VERSION 5.7 ;
  NOWIREEXTENSIONATPIN ON ;
  DIVIDERCHAR "/" ;
  BUSBITCHARS "[]" ;
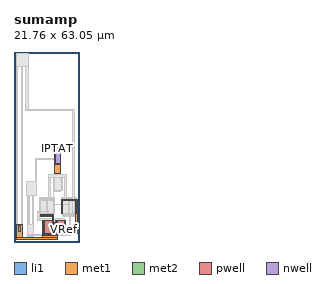
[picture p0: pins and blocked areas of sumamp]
MACRO sumamp
  CLASS BLOCK ;
  FOREIGN sumamp ;
  ORIGIN -0.630 -0.510 ;
  SIZE 21.760 BY 63.050 ;
  PIN IPTAT
    ANTENNAGATEAREA 4.000000 ;
    PORT
      LAYER li1 ;
        RECT 14.485 30.945 15.485 31.175 ;
      LAYER met1 ;
        RECT 14.015 30.920 15.935 32.040 ;
    END
  END IPTAT
  PIN VRef
    ANTENNAGATEAREA 16.000000 ;
    ANTENNADIFFAREA 3.180000 ;
    PORT
      LAYER li1 ;
        RECT 16.485 10.110 16.655 14.110 ;
        RECT 21.045 10.110 21.215 14.110 ;
        RECT 9.485 9.270 13.765 9.500 ;
        RECT 17.305 3.370 17.475 7.370 ;
      LAYER met1 ;
        RECT 16.455 14.460 21.245 14.510 ;
        RECT 16.455 14.280 21.725 14.460 ;
        RECT 16.455 10.110 16.685 14.280 ;
        RECT 21.015 10.110 21.725 14.280 ;
        RECT 9.485 9.250 13.765 9.520 ;
        RECT 9.495 8.850 13.735 9.250 ;
        RECT 13.515 5.445 14.055 7.130 ;
        RECT 17.275 5.755 17.505 7.370 ;
        RECT 21.150 5.755 21.725 10.110 ;
        RECT 17.275 3.370 21.725 5.755 ;
        RECT 17.345 3.240 21.725 3.370 ;
      LAYER met2 ;
        RECT 13.515 9.235 13.685 9.250 ;
        RECT 13.435 8.915 13.695 9.235 ;
        RECT 13.515 5.810 13.685 8.915 ;
        RECT 13.515 5.660 13.815 5.810 ;
        RECT 17.860 5.660 18.120 5.735 ;
        RECT 13.515 5.455 18.120 5.660 ;
        RECT 13.515 5.450 13.685 5.455 ;
        RECT 17.860 5.415 18.120 5.455 ;
    END
  END VRef
  PIN GND
    ANTENNADIFFAREA 4.440000 ;
    PORT
      LAYER pwell ;
        RECT 9.985 3.240 13.335 7.500 ;
        RECT 14.295 3.240 17.645 7.500 ;
      LAYER li1 ;
        RECT 2.285 3.990 2.635 6.150 ;
        RECT 10.125 3.370 10.395 7.370 ;
        RECT 10.715 3.370 10.885 7.370 ;
        RECT 14.435 3.370 14.705 7.370 ;
        RECT 15.025 3.370 15.195 7.370 ;
      LAYER met1 ;
        RECT 1.560 1.865 3.475 6.305 ;
        RECT 10.125 5.105 10.395 7.370 ;
        RECT 10.685 5.105 10.915 7.370 ;
        RECT 14.435 5.245 14.705 7.370 ;
        RECT 14.995 5.245 15.225 7.370 ;
        RECT 9.970 3.370 10.915 5.105 ;
        RECT 14.305 3.370 15.225 5.245 ;
        RECT 9.970 2.970 10.870 3.370 ;
        RECT 14.305 2.970 15.170 3.370 ;
        RECT 9.970 2.620 15.170 2.970 ;
        RECT 9.970 1.865 15.175 2.620 ;
        RECT 1.560 1.375 15.215 1.865 ;
        RECT 1.585 1.370 15.215 1.375 ;
    END
  END GND
  PIN VDD
    ANTENNADIFFAREA 1.503700 ;
    PORT
      LAYER nwell ;
        RECT 14.040 25.925 15.930 30.915 ;
      LAYER li1 ;
        RECT 14.260 26.735 14.430 30.735 ;
        RECT 14.230 26.115 15.740 26.385 ;
      LAYER met1 ;
        RECT 14.230 26.735 14.460 30.735 ;
        RECT 14.260 26.505 14.460 26.735 ;
        RECT 14.030 23.345 15.930 26.505 ;
    END
  END VDD
  OBS
      LAYER pwell ;
        RECT 1.505 61.500 3.415 61.930 ;
        RECT 1.505 3.640 1.935 61.500 ;
        RECT 2.985 3.640 3.415 61.500 ;
        RECT 1.505 3.210 3.415 3.640 ;
        RECT 5.235 18.510 7.145 18.940 ;
        RECT 5.235 3.650 5.665 18.510 ;
        RECT 6.715 3.650 7.145 18.510 ;
      LAYER nwell ;
        RECT 13.765 17.490 16.655 22.480 ;
        RECT 9.040 9.930 14.210 15.160 ;
        RECT 16.265 9.930 21.435 15.160 ;
      LAYER pwell ;
        RECT 5.235 3.220 7.145 3.650 ;
      LAYER li1 ;
        RECT 1.635 61.630 3.285 61.800 ;
        RECT 1.635 3.510 1.805 61.630 ;
        RECT 2.285 58.990 2.635 61.150 ;
        RECT 3.115 3.510 3.285 61.630 ;
        RECT 15.540 26.735 15.710 30.735 ;
        RECT 13.955 22.020 16.465 22.290 ;
        RECT 1.635 3.340 3.285 3.510 ;
        RECT 5.365 18.640 7.015 18.810 ;
        RECT 5.365 3.520 5.535 18.640 ;
        RECT 6.015 16.000 6.365 18.160 ;
        RECT 6.015 4.000 6.365 6.160 ;
        RECT 6.845 3.520 7.015 18.640 ;
        RECT 13.985 17.670 14.155 21.670 ;
        RECT 16.265 17.670 16.435 21.670 ;
        RECT 14.210 17.230 16.210 17.460 ;
        RECT 9.230 14.700 14.020 14.970 ;
        RECT 16.455 14.700 21.245 14.970 ;
        RECT 9.260 10.110 9.430 14.110 ;
        RECT 11.540 10.110 11.710 14.110 ;
        RECT 13.820 10.110 13.990 14.110 ;
        RECT 18.765 10.110 18.935 14.110 ;
        RECT 16.710 9.270 20.990 9.500 ;
        RECT 10.940 7.580 12.940 7.810 ;
        RECT 15.250 7.580 17.250 7.810 ;
        RECT 5.365 3.350 7.015 3.520 ;
        RECT 12.995 3.370 13.165 7.370 ;
      LAYER met1 ;
        RECT 1.515 63.150 4.955 63.180 ;
        RECT 1.515 58.755 5.305 63.150 ;
        RECT 4.335 44.590 5.305 58.755 ;
        RECT 4.330 44.190 20.530 44.590 ;
        RECT 4.335 44.170 5.305 44.190 ;
        RECT 15.510 28.430 15.740 30.735 ;
        RECT 15.510 28.300 15.895 28.430 ;
        RECT 7.715 20.590 8.005 28.295 ;
        RECT 15.510 27.980 15.935 28.300 ;
        RECT 15.510 27.745 15.895 27.980 ;
        RECT 15.510 26.735 15.740 27.745 ;
        RECT 4.670 15.850 8.005 20.590 ;
        RECT 12.095 22.020 18.185 22.935 ;
        RECT 12.095 14.970 12.760 22.020 ;
        RECT 13.955 18.590 14.185 21.670 ;
        RECT 16.225 21.440 16.500 22.020 ;
        RECT 13.610 17.670 14.185 18.590 ;
        RECT 16.235 17.670 16.465 21.440 ;
        RECT 13.610 17.500 14.155 17.670 ;
        RECT 13.610 17.480 14.455 17.500 ;
        RECT 13.610 17.210 16.210 17.480 ;
        RECT 13.610 17.165 14.455 17.210 ;
        RECT 17.495 14.970 18.160 22.020 ;
        RECT 9.230 14.700 14.020 14.970 ;
        RECT 16.455 14.700 21.245 14.970 ;
        RECT 9.230 14.280 14.020 14.510 ;
        RECT 8.335 8.235 8.980 10.670 ;
        RECT 9.230 10.110 9.460 14.280 ;
        RECT 11.510 10.880 11.740 14.110 ;
        RECT 13.790 13.135 14.020 14.280 ;
        RECT 18.735 13.135 18.965 14.110 ;
        RECT 13.605 12.775 14.180 13.135 ;
        RECT 18.570 12.775 19.145 13.135 ;
        RECT 11.350 10.285 11.925 10.880 ;
        RECT 11.510 9.710 11.740 10.285 ;
        RECT 13.790 10.110 14.020 12.775 ;
        RECT 18.735 9.710 18.965 12.775 ;
        RECT 20.250 10.350 20.510 10.670 ;
        RECT 16.710 9.250 20.990 9.520 ;
        RECT 16.730 8.850 20.970 9.250 ;
        RECT 8.335 7.565 17.260 8.235 ;
        RECT 10.940 7.560 13.210 7.565 ;
        RECT 15.250 7.560 17.250 7.565 ;
        RECT 5.120 2.210 7.200 6.320 ;
        RECT 12.925 5.550 13.210 7.560 ;
        RECT 12.965 3.370 13.195 5.550 ;
      LAYER met2 ;
        RECT 15.675 28.270 15.935 28.300 ;
        RECT 7.675 27.980 15.935 28.270 ;
        RECT 7.675 27.895 15.885 27.980 ;
        RECT 7.735 27.890 7.995 27.895 ;
        RECT 13.610 18.260 13.765 18.590 ;
        RECT 13.610 17.940 13.940 18.260 ;
        RECT 13.610 13.115 13.765 17.940 ;
        RECT 13.610 13.000 13.930 13.115 ;
        RECT 18.680 13.000 18.940 13.095 ;
        RECT 13.610 12.855 19.000 13.000 ;
        RECT 13.610 12.795 13.930 12.855 ;
        RECT 13.610 12.790 13.765 12.795 ;
        RECT 18.680 12.775 18.940 12.855 ;
        RECT 11.555 10.665 11.815 10.780 ;
        RECT 8.335 10.520 11.925 10.665 ;
        RECT 8.515 10.305 8.775 10.520 ;
        RECT 11.555 10.460 11.815 10.520 ;
        RECT 20.205 10.400 20.555 44.620 ;
        RECT 20.250 10.350 20.510 10.400 ;
        RECT 19.100 3.110 19.400 9.390 ;
        RECT 5.270 2.730 19.400 3.110 ;
  END
END sumamp
END LIBRARY

